VERSION 5.7 ;
  NOWIREEXTENSIONATPIN ON ;
  DIVIDERCHAR "/" ;
  BUSBITCHARS "[]" ;
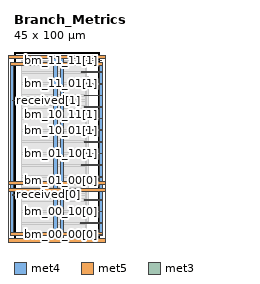
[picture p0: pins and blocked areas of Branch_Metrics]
MACRO Branch_Metrics
  CLASS BLOCK ;
  FOREIGN Branch_Metrics ;
  ORIGIN 0.000 0.000 ;
  SIZE 45.000 BY 100.000 ;
  PIN VGND
    DIRECTION INOUT ;
    USE GROUND ;
    PORT
      LAYER met4 ;
        RECT -5.380 -0.020 -3.780 97.940 ;
    END
    PORT
      LAYER met5 ;
        RECT -5.380 -0.020 50.000 1.580 ;
    END
    PORT
      LAYER met5 ;
        RECT -5.380 96.340 50.000 97.940 ;
    END
    PORT
      LAYER met4 ;
        RECT 48.400 -0.020 50.000 97.940 ;
    END
    PORT
      LAYER met4 ;
        RECT 24.340 -0.020 25.940 97.940 ;
    END
    PORT
      LAYER met5 ;
        RECT -5.380 30.030 50.000 31.630 ;
    END
  END VGND
  PIN VPWR
    DIRECTION INOUT ;
    USE POWER ;
    PORT
      LAYER met4 ;
        RECT -2.080 3.280 -0.480 94.640 ;
    END
    PORT
      LAYER met5 ;
        RECT -2.080 3.280 46.700 4.880 ;
    END
    PORT
      LAYER met5 ;
        RECT -2.080 93.040 46.700 94.640 ;
    END
    PORT
      LAYER met4 ;
        RECT 45.100 3.280 46.700 94.640 ;
    END
    PORT
      LAYER met4 ;
        RECT 21.040 -0.020 22.640 97.940 ;
    END
    PORT
      LAYER met5 ;
        RECT -5.380 26.730 50.000 28.330 ;
    END
  END VPWR
  PIN bm_00_00[0]
    DIRECTION OUTPUT ;
    USE SIGNAL ;
    ANTENNADIFFAREA 0.445500 ;
    PORT
      LAYER met3 ;
        RECT 37.170 3.590 46.000 3.890 ;
    END
  END bm_00_00[0]
  PIN bm_00_00[1]
    DIRECTION OUTPUT ;
    USE SIGNAL ;
    ANTENNADIFFAREA 0.445500 ;
    PORT
      LAYER met3 ;
        RECT 34.870 9.710 46.000 10.010 ;
    END
  END bm_00_00[1]
  PIN bm_00_10[0]
    DIRECTION OUTPUT ;
    USE SIGNAL ;
    ANTENNADIFFAREA 0.445500 ;
    PORT
      LAYER met3 ;
        RECT 37.170 15.830 46.000 16.130 ;
    END
  END bm_00_10[0]
  PIN bm_00_10[1]
    DIRECTION OUTPUT ;
    USE SIGNAL ;
    ANTENNADIFFAREA 0.445500 ;
    PORT
      LAYER met3 ;
        RECT 37.170 21.950 46.000 22.250 ;
    END
  END bm_00_10[1]
  PIN bm_01_00[0]
    DIRECTION OUTPUT ;
    USE SIGNAL ;
    ANTENNADIFFAREA 0.445500 ;
    PORT
      LAYER met3 ;
        RECT 37.170 28.070 46.000 28.370 ;
    END
  END bm_01_00[0]
  PIN bm_01_00[1]
    DIRECTION OUTPUT ;
    USE SIGNAL ;
    ANTENNADIFFAREA 0.445500 ;
    PORT
      LAYER met3 ;
        RECT 37.170 34.190 46.000 34.490 ;
    END
  END bm_01_00[1]
  PIN bm_01_10[0]
    DIRECTION OUTPUT ;
    USE SIGNAL ;
    ANTENNADIFFAREA 0.445500 ;
    PORT
      LAYER met3 ;
        RECT 35.330 40.310 46.000 40.610 ;
    END
  END bm_01_10[0]
  PIN bm_01_10[1]
    DIRECTION OUTPUT ;
    USE SIGNAL ;
    ANTENNADIFFAREA 0.445500 ;
    PORT
      LAYER met3 ;
        RECT 37.170 46.430 46.000 46.730 ;
    END
  END bm_01_10[1]
  PIN bm_10_01[0]
    DIRECTION OUTPUT ;
    USE SIGNAL ;
    ANTENNADIFFAREA 0.445500 ;
    PORT
      LAYER met3 ;
        RECT 37.170 52.550 46.000 52.850 ;
    END
  END bm_10_01[0]
  PIN bm_10_01[1]
    DIRECTION OUTPUT ;
    USE SIGNAL ;
    ANTENNADIFFAREA 0.445500 ;
    PORT
      LAYER met3 ;
        RECT 37.170 58.670 46.000 58.970 ;
    END
  END bm_10_01[1]
  PIN bm_10_11[0]
    DIRECTION OUTPUT ;
    USE SIGNAL ;
    ANTENNADIFFAREA 0.445500 ;
    PORT
      LAYER met3 ;
        RECT 33.490 64.790 46.000 65.090 ;
    END
  END bm_10_11[0]
  PIN bm_10_11[1]
    DIRECTION OUTPUT ;
    USE SIGNAL ;
    ANTENNADIFFAREA 0.445500 ;
    PORT
      LAYER met3 ;
        RECT 37.170 70.910 46.000 71.210 ;
    END
  END bm_10_11[1]
  PIN bm_11_01[0]
    DIRECTION OUTPUT ;
    USE SIGNAL ;
    ANTENNADIFFAREA 0.445500 ;
    PORT
      LAYER met3 ;
        RECT 37.170 77.030 46.000 77.330 ;
    END
  END bm_11_01[0]
  PIN bm_11_01[1]
    DIRECTION OUTPUT ;
    USE SIGNAL ;
    ANTENNADIFFAREA 0.445500 ;
    PORT
      LAYER met3 ;
        RECT 37.170 83.150 46.000 83.450 ;
    END
  END bm_11_01[1]
  PIN bm_11_11[0]
    DIRECTION OUTPUT ;
    USE SIGNAL ;
    ANTENNADIFFAREA 0.445500 ;
    PORT
      LAYER met3 ;
        RECT 35.330 89.270 46.000 89.570 ;
    END
  END bm_11_11[0]
  PIN bm_11_11[1]
    DIRECTION OUTPUT ;
    USE SIGNAL ;
    ANTENNADIFFAREA 0.445500 ;
    PORT
      LAYER met3 ;
        RECT 37.630 95.390 46.000 95.690 ;
    END
  END bm_11_11[1]
  PIN received[0]
    DIRECTION INPUT ;
    USE SIGNAL ;
    ANTENNAGATEAREA 0.213000 ;
    PORT
      LAYER met3 ;
        RECT -1.000 24.670 4.230 24.970 ;
    END
  END received[0]
  PIN received[1]
    DIRECTION INPUT ;
    USE SIGNAL ;
    ANTENNAGATEAREA 0.213000 ;
    PORT
      LAYER met3 ;
        RECT -1.000 74.310 4.230 74.610 ;
    END
  END received[1]
  OBS
      LAYER nwell ;
        RECT 5.330 10.795 39.290 87.125 ;
      LAYER li1 ;
        RECT 5.520 10.795 39.100 87.125 ;
      LAYER met1 ;
        RECT 4.210 10.640 39.100 87.280 ;
      LAYER met2 ;
        RECT 4.230 3.555 38.080 95.725 ;
      LAYER met3 ;
        RECT 4.205 94.990 37.230 95.705 ;
        RECT 4.205 89.970 37.655 94.990 ;
        RECT 4.205 88.870 34.930 89.970 ;
        RECT 4.205 83.850 37.655 88.870 ;
        RECT 4.205 82.750 36.770 83.850 ;
        RECT 4.205 77.730 37.655 82.750 ;
        RECT 4.205 76.630 36.770 77.730 ;
        RECT 4.205 75.010 37.655 76.630 ;
        RECT 4.630 73.910 37.655 75.010 ;
        RECT 4.205 71.610 37.655 73.910 ;
        RECT 4.205 70.510 36.770 71.610 ;
        RECT 4.205 65.490 37.655 70.510 ;
        RECT 4.205 64.390 33.090 65.490 ;
        RECT 4.205 59.370 37.655 64.390 ;
        RECT 4.205 58.270 36.770 59.370 ;
        RECT 4.205 53.250 37.655 58.270 ;
        RECT 4.205 52.150 36.770 53.250 ;
        RECT 4.205 47.130 37.655 52.150 ;
        RECT 4.205 46.030 36.770 47.130 ;
        RECT 4.205 41.010 37.655 46.030 ;
        RECT 4.205 39.910 34.930 41.010 ;
        RECT 4.205 34.890 37.655 39.910 ;
        RECT 4.205 33.790 36.770 34.890 ;
        RECT 4.205 28.770 37.655 33.790 ;
        RECT 4.205 27.670 36.770 28.770 ;
        RECT 4.205 25.370 37.655 27.670 ;
        RECT 4.630 24.270 37.655 25.370 ;
        RECT 4.205 22.650 37.655 24.270 ;
        RECT 4.205 21.550 36.770 22.650 ;
        RECT 4.205 16.530 37.655 21.550 ;
        RECT 4.205 15.430 36.770 16.530 ;
        RECT 4.205 10.410 37.655 15.430 ;
        RECT 4.205 9.310 34.470 10.410 ;
        RECT 4.205 4.290 37.655 9.310 ;
        RECT 4.205 3.575 36.770 4.290 ;
  END
END Branch_Metrics
END LIBRARY

